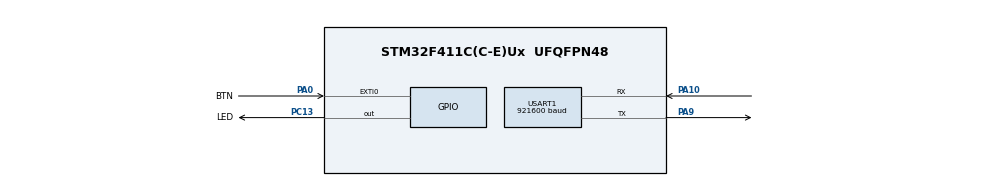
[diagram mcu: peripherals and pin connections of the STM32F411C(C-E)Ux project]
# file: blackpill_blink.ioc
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Mcu.Family=STM32F4
Mcu.Name=STM32F411C(C-E)Ux
Mcu.Package=UFQFPN48
NVIC.EXTI0_IRQn=true\:0\:0\:false\:false\:true\:true\:true\:true
NVIC.PriorityGroup=NVIC_PRIORITYGROUP_4
PA0-WKUP.GPIO_Label=BTN
PA0-WKUP.GPIO_ModeDefaultEXTI=GPIO_MODE_IT_FALLING
PA0-WKUP.GPIO_PuPd=GPIO_PULLUP
PA0-WKUP.Signal=GPXTI0
PA10.Mode=Asynchronous
PA10.Signal=USART1_RX
PA13.Mode=Serial_Wire
PA13.Signal=SYS_JTMS-SWDIO
PA14.Mode=Serial_Wire
PA14.Signal=SYS_JTCK-SWCLK
PA9.Mode=Asynchronous
PA9.Signal=USART1_TX
PC13-ANTI_TAMP.GPIO_Label=LED
PC13-ANTI_TAMP.GPIO_ModeDefaultOutputPP=GPIO_MODE_OUTPUT_OD
PC13-ANTI_TAMP.GPIO_PuPd=GPIO_NOPULL
PC13-ANTI_TAMP.PinState=GPIO_PIN_SET
PC13-ANTI_TAMP.Signal=GPIO_Output
PH0\ -\ OSC_IN.Mode=HSE-External-Oscillator
PH0\ -\ OSC_IN.Signal=RCC_OSC_IN
PH1\ -\ OSC_OUT.Mode=HSE-External-Oscillator
PH1\ -\ OSC_OUT.Signal=RCC_OSC_OUT
ProjectManager.HeapSize=0x200
ProjectManager.StackSize=0x400
ProjectManager.TargetToolchain=STM32CubeIDE
RCC.48MHZClocksFreq_Value=50000000
RCC.AHBFreq_Value=100000000
RCC.APB1CLKDivider=RCC_HCLK_DIV2
RCC.APB1Freq_Value=50000000
RCC.APB1TimFreq_Value=100000000
RCC.APB2Freq_Value=100000000
RCC.APB2TimFreq_Value=100000000
RCC.CortexFreq_Value=100000000
RCC.HCLKFreq_Value=100000000
RCC.HSE_VALUE=25000000
RCC.HSI_VALUE=16000000
RCC.LSE_VALUE=32768
RCC.PLLM=12
RCC.PLLN=96
RCC.PLLSourceVirtual=RCC_PLLSOURCE_HSE
RCC.SYSCLKFreq_VALUE=100000000
RCC.SYSCLKSource=RCC_SYSCLKSOURCE_PLLCLK
RCC.VCOOutputFreq_Value=200000000
USART1.BaudRate=921600
USART1.VirtualMode=VM_ASYNC
board=custom

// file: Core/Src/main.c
/* USER CODE BEGIN Header */
/**
  ******************************************************************************
  * @file           : main.c
  * @brief          : Main program body
  ******************************************************************************
  * @attention
  *
  * Copyright (c) 2025 STMicroelectronics.
  * All rights reserved.
  *
  * This software is licensed under terms that can be found in the LICENSE file
  * in the root directory of this software component.
  * If no LICENSE file comes with this software, it is provided AS-IS.
  *
  ******************************************************************************
  */
/* USER CODE END Header */
#include "main.h"
#include <stdio.h>

UART_HandleTypeDef huart1;

void SystemClock_Config(void);
static void MX_GPIO_Init(void);
static void MX_USART1_UART_Init(void);

/* USER CODE BEGIN 0 */

// Send printf to uart1
int _write(int fd, char *ptr, int len) {
    HAL_StatusTypeDef hstatus;

    if (fd == 1 || fd == 2) {
        hstatus = HAL_UART_Transmit(&huart1, (uint8_t*) ptr, len, HAL_MAX_DELAY);
        if (hstatus == HAL_OK)
            return len;
        else
            return -1;
    }
    return -1;
}

/* USER CODE END 0 */

int main(void)
{

  /* MCU Configuration--------------------------------------------------------*/

  /* Reset of all peripherals, Initializes the Flash interface and the Systick. */
  HAL_Init();

  /* Configure the system clock */
  SystemClock_Config();

  /* Initialize all configured peripherals */
  MX_GPIO_Init();
  MX_USART1_UART_Init();

  /* Infinite loop */
  /* USER CODE BEGIN WHILE */
  uint32_t now = 0, last_tick = 0, last_toggle = 0;

  while (1)
  {
	  now = HAL_GetTick();
	  if (now - last_tick >= 500) {
		  HAL_GPIO_TogglePin(LED_GPIO_Port, LED_Pin);
		  last_tick += 500;
	  }
    /* USER CODE END WHILE */

  }
}

void SystemClock_Config(void)
{
  RCC_OscInitTypeDef RCC_OscInitStruct = {0};
  RCC_ClkInitTypeDef RCC_ClkInitStruct = {0};

  /** Configure the main internal regulator output voltage
  */
  __HAL_RCC_PWR_CLK_ENABLE();
  __HAL_PWR_VOLTAGESCALING_CONFIG(PWR_REGULATOR_VOLTAGE_SCALE1);

  /** Initializes the RCC Oscillators according to the specified parameters
  * in the RCC_OscInitTypeDef structure.
  */
  RCC_OscInitStruct.OscillatorType = RCC_OSCILLATORTYPE_HSE;
  RCC_OscInitStruct.HSEState = RCC_HSE_ON;
  RCC_OscInitStruct.PLL.PLLState = RCC_PLL_ON;
  RCC_OscInitStruct.PLL.PLLSource = RCC_PLLSOURCE_HSE;
  RCC_OscInitStruct.PLL.PLLM = 15;
  RCC_OscInitStruct.PLL.PLLN = 96;
  RCC_OscInitStruct.PLL.PLLP = RCC_PLLP_DIV2;
  RCC_OscInitStruct.PLL.PLLQ = 4;
  if (HAL_RCC_OscConfig(&RCC_OscInitStruct) != HAL_OK)
  {
    Error_Handler();
  }

  /** Initializes the CPU, AHB and APB buses clocks
  */
  RCC_ClkInitStruct.ClockType = RCC_CLOCKTYPE_HCLK|RCC_CLOCKTYPE_SYSCLK
                              |RCC_CLOCKTYPE_PCLK1|RCC_CLOCKTYPE_PCLK2;
  RCC_ClkInitStruct.SYSCLKSource = RCC_SYSCLKSOURCE_PLLCLK;
  RCC_ClkInitStruct.AHBCLKDivider = RCC_SYSCLK_DIV8;
  RCC_ClkInitStruct.APB1CLKDivider = RCC_HCLK_DIV2;
  RCC_ClkInitStruct.APB2CLKDivider = RCC_HCLK_DIV1;

  if (HAL_RCC_ClockConfig(&RCC_ClkInitStruct, FLASH_LATENCY_0) != HAL_OK)
  {
    Error_Handler();
  }
}

static void MX_USART1_UART_Init(void)
{

  huart1.Instance = USART1;
  huart1.Init.BaudRate = 300;
  huart1.Init.WordLength = UART_WORDLENGTH_8B;
  huart1.Init.StopBits = UART_STOPBITS_1;
  huart1.Init.Parity = UART_PARITY_NONE;
  huart1.Init.Mode = UART_MODE_TX_RX;
  huart1.Init.HwFlowCtl = UART_HWCONTROL_NONE;
  huart1.Init.OverSampling = UART_OVERSAMPLING_16;
  if (HAL_UART_Init(&huart1) != HAL_OK)
  {
    Error_Handler();
  }

}

static void MX_GPIO_Init(void)
{
  GPIO_InitTypeDef GPIO_InitStruct = {0};

  /* GPIO Ports Clock Enable */
  __HAL_RCC_GPIOC_CLK_ENABLE();
  __HAL_RCC_GPIOH_CLK_ENABLE();
  __HAL_RCC_GPIOA_CLK_ENABLE();

  /*Configure GPIO pin Output Level */
  HAL_GPIO_WritePin(LED_GPIO_Port, LED_Pin, GPIO_PIN_SET);

  /*Configure GPIO pin : LED_Pin */
  GPIO_InitStruct.Pin = LED_Pin;
  GPIO_InitStruct.Mode = GPIO_MODE_OUTPUT_OD;
  GPIO_InitStruct.Pull = GPIO_NOPULL;
  GPIO_InitStruct.Speed = GPIO_SPEED_FREQ_LOW;
  HAL_GPIO_Init(LED_GPIO_Port, &GPIO_InitStruct);

  /*Configure GPIO pin : BTN_Pin */
  GPIO_InitStruct.Pin = BTN_Pin;
  GPIO_InitStruct.Mode = GPIO_MODE_IT_RISING_FALLING;
  GPIO_InitStruct.Pull = GPIO_PULLUP;
  HAL_GPIO_Init(BTN_GPIO_Port, &GPIO_InitStruct);

}

void Error_Handler(void)
{
  __disable_irq();
  while (1)
  {
  }
}
